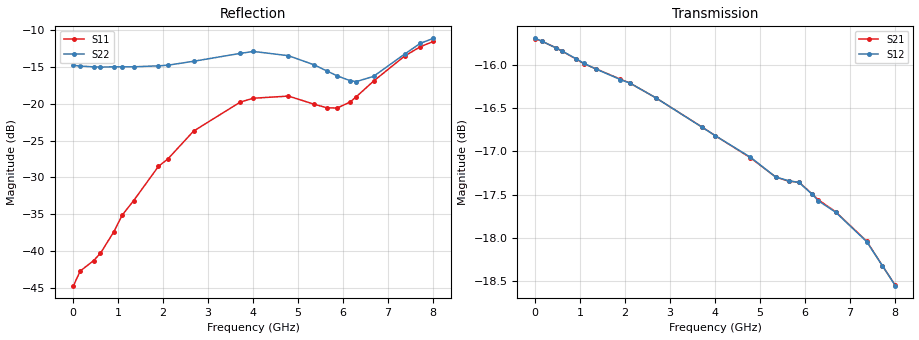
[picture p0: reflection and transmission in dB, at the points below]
! DEVICE ID: PE43712
! File Path: z:\PE43713\PE43713_CHAR_NOM_04292014\AMB\3p300\LS_ATT_14p50dB\PE43713_AMB_3p300V_3p000V_0p000V_LS_ATT_14p50dB_S2P_SN_10_A0139A.s2p
! Serial: 10
! Lot: A0139A
! Temp: 25C
! VDD: 3.300
! VSS: 0.000
! Control_Hi: 3.000
! Control_Lo: 0.000
! Attenuation Step: 14.50dB
! Port 1: RF1
! Port 2: RF2
! ThroughPath:1-2
! IDD: 0.0001472736
! ISS: -8.72e-008
#  Hz  S  RI  R  50
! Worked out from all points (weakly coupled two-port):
!   801 points, 10 MHz to 8.01 GHz, reference 50 ohm
!   highest |S21| = -15.70 dB at 10 MHz (marker M1); lowest = -18.5 dB at 8.01 GHz (marker M2)
!   lowest |S11| = -44.8 dB at 10 MHz (marker M3), VSWR 1.01, Z = 50.6 + j0.0437 ohm
!   |S11| at or under -10 dB: start of sweep to end of sweep
!   |S22| runs from -17.0 to -11.1 dB; largest |S21 - S12| = 0.00059
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1e7  0.00577 0.000432  0.1641 -0.000799  0.1642 -0.000838  -0.1829 0.00116
1.6e8  0.0069 0.0023  0.1632 -0.0108  0.1632 -0.0108  -0.1807 0.012
4.6e8  0.00693 0.00507  0.1594 -0.0299  0.1594 -0.0298  -0.1763 0.0297
6.1e8  0.00637 0.0072  0.1567 -0.0387  0.1567 -0.0387  -0.1735 0.0394
9.1e8  0.00535 0.0124  0.1498 -0.0555  0.1499 -0.0555  -0.1694 0.0577
1.09e9  0.00532 0.0166  0.1449 -0.0648  0.145 -0.0648  -0.1649 0.0695
1.35e9  0.00621 0.0211  0.1374 -0.0774  0.1373 -0.0775  -0.1582 0.0837
1.9e9  0.0117 0.0357  0.1179 -0.1014  0.1178 -0.1014  -0.1381 0.1181
2.11e9  0.0141 0.0398  0.1093 -0.1095  0.1093 -0.1095  -0.1308 0.1287
2.68e9  0.0255 0.0601  0.0832 -0.1269  0.0832 -0.1269  -0.1013 0.1668
3.72e9  0.0319 0.0979  0.0303 -0.1427  0.0302 -0.1427  -0.0682 0.21
4.01e9  0.0318 0.1046  0.0155 -0.1434  0.0155 -0.1434  -0.0648 0.2182
4.79e9  0.0321 0.1084  -0.0222 -0.1383  -0.0222 -0.1384  -0.0448 0.2082
5.35e9  0.0432 0.0899  -0.0464 -0.1284  -0.0464 -0.1284  -0.0244 0.1834
5.64e9  0.0535 0.0775  -0.0579 -0.1228  -0.0579 -0.1229  -0.0027 0.1678
5.87e9  0.0634 0.069  -0.068 -0.1173  -0.0679 -0.1173  0.0182 0.1543
6.16e9  0.0813 0.0632  -0.0794 -0.1073  -0.0792 -0.1074  0.0496 0.1351
6.3e9  0.094 0.0611  -0.0835 -0.1028  -0.0832 -0.1028  0.0669 0.1252
6.68e9  0.1297 0.0601  -0.0948 -0.0895  -0.0946 -0.0896  0.1134 0.1042
7.37e9  0.1994 0.0707  -0.1102 -0.0598  -0.1101 -0.0598  0.1946 0.0988
7.72e9  0.2319 0.0794  -0.1127 -0.045  -0.1127 -0.045  0.2363 0.1049
8.01e9  0.2505 0.09  -0.1133 -0.0336  -0.1132 -0.0338  0.2579 0.1076
